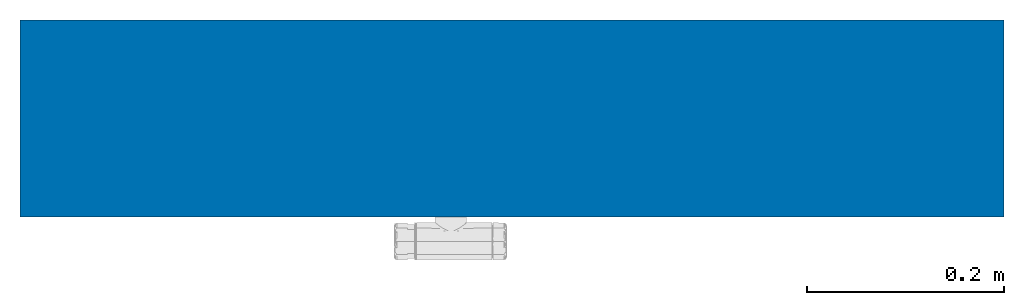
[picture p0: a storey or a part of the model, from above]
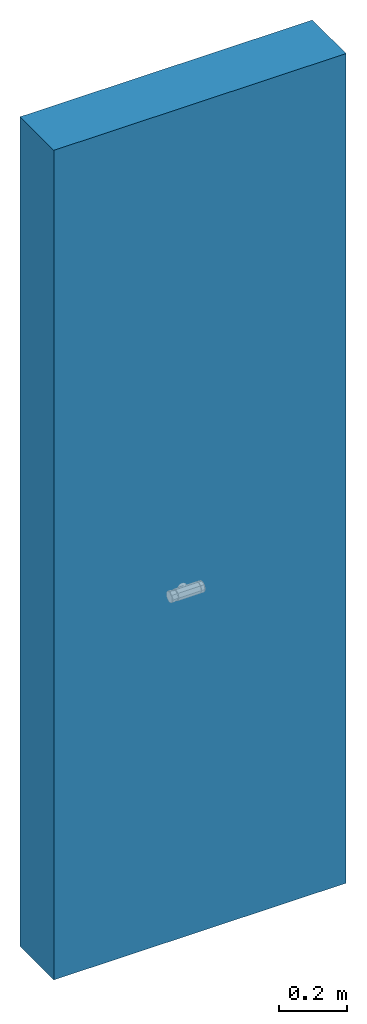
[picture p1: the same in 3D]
Properties of the parts of a building model (IFC2X3)

# File
Description: ViewDefinition [CoordinationView]
File name: Project Number
Time: 2016-07-07T13:59:06
Written by: Autodesk Revit Architecture 2011 - 1.0
Made in: 20100326_1700(x64)

# IfcProject, Project Number
Phase: Project Status

# IfcSite, Default
RefLatitude: 42, 21, 30, 344238; RefLongitude: -71, -3, -35, -194702; RefElevation: 0 mm

# IfcBuilding
Pset_BuildingCommon - NumberOfStoreys: 1
PSet_Revit_Other - Project Issue Date: Issue Date; Project Status: Project Status; Client Name: Owner; Project Address: Enter address here; Project Name: Project Name; Project Number: Project Number

# IfcBuildingStorey, Level 1
Elevation: 0 mm
PSet_Revit_Identity Data - Name: Level 1
PSet_Revit_Constraints - Elevation: 0 mm
PSet_Revit_Type_Graphics - Line Weight: 1; Color: 0; Line Pattern: Centre; Symbol: M_Level Head - Circle; Symbol at End 1 Default: no; Symbol at End 2 Default: yes
PSet_Revit_Type_Constraints - Elevation Base: 0
PSet_Revit_Type_Dimensions - Automatic Room Computation Height: no; Computation Height: 1200 mm

# IfcBuildingElementProxy: Type 1, 761000:Type 1:Type 1:174286
In: Level 1
PSet_Revit_Constraints - Level: Level 1; Elevation: 1247.59 mm
PSet_Revit_Phasing - Phase Created: New Construction
PSet_Revit_Type_Identity Data - Technologie: Temporisée; Référence: 761000; Raccordement: M3/4"; Lien notice d'installation: www.delabie.fr/produits/761000; Lien fiche produit: www.delabie.fr/produits/761000; Lien certification: www.delabie.fr/produits/761000; Lien CCTP: www.delabie.fr/produits/761000; Finition: Laiton massif chromé; Famille de produits: WC; Description: DELABIE, fabricant français, est le leader européen de l'équipement sanitaire pour les établissements recevant du public. Robinetteries, solutions pour personnes à mobilité réduite, appareils sanitaires, destinés aux écoles, lieux de loisirs, bureaux, hôpitaux, aéroports, ...; Type Comments: Robinet temporisé de chasse directe; Model: TEMPOFLUX; Manufacturer: DELABIE; URL: http://www.delabie.fr/; Descriptif: Robinet temporisé de chasse directe à poser en applique : Déclenchement souple. Temporisation ~7 sec. Protection antisiphonique. Corps et bouton en laiton massif chromé. Alimentation équerre M3/4". Avec écrou de sortie Ø 28.
PSet_Revit_Type_Dimensions - Radius: 13 mm

# IfcWallStandardCase: Basic Wall:Generic - 200mm:398, Basic Wall:Generic - 200mm:127588
In: Level 1
Material: Default Wall 200 mm
Pset_WallCommon - Reference: Basic Wall:Generic - 200mm; LoadBearing: no; ExtendToStructure: no; IsExternal: yes
PSet_Revit_Constraints - Location Line: 0; Base Constraint: Level 1; Base Offset: 0 mm; Base is Attached: no; Base Extension Distance: 0 mm; Unconnected Height: 3000 mm; Top Offset: 0 mm; Top is Attached: no; Top Extension Distance: 0 mm; Room Bounding: yes; Related to Mass: no
PSet_Revit_Phasing - Phase Created: New Construction
PSet_Revit_Structural - Structural Usage: 0
PSet_Revit_Dimensions - Length: 1000 mm; Area: 3000000 mm2; Volume: 600000000 mm3
PSet_Revit_Type_Construction - Wrapping at Inserts: 0; Wrapping at Ends: 0; Width: 200 mm; Function: 1
PSet_Revit_Type_Graphics - Coarse Scale Fill Color: 0
